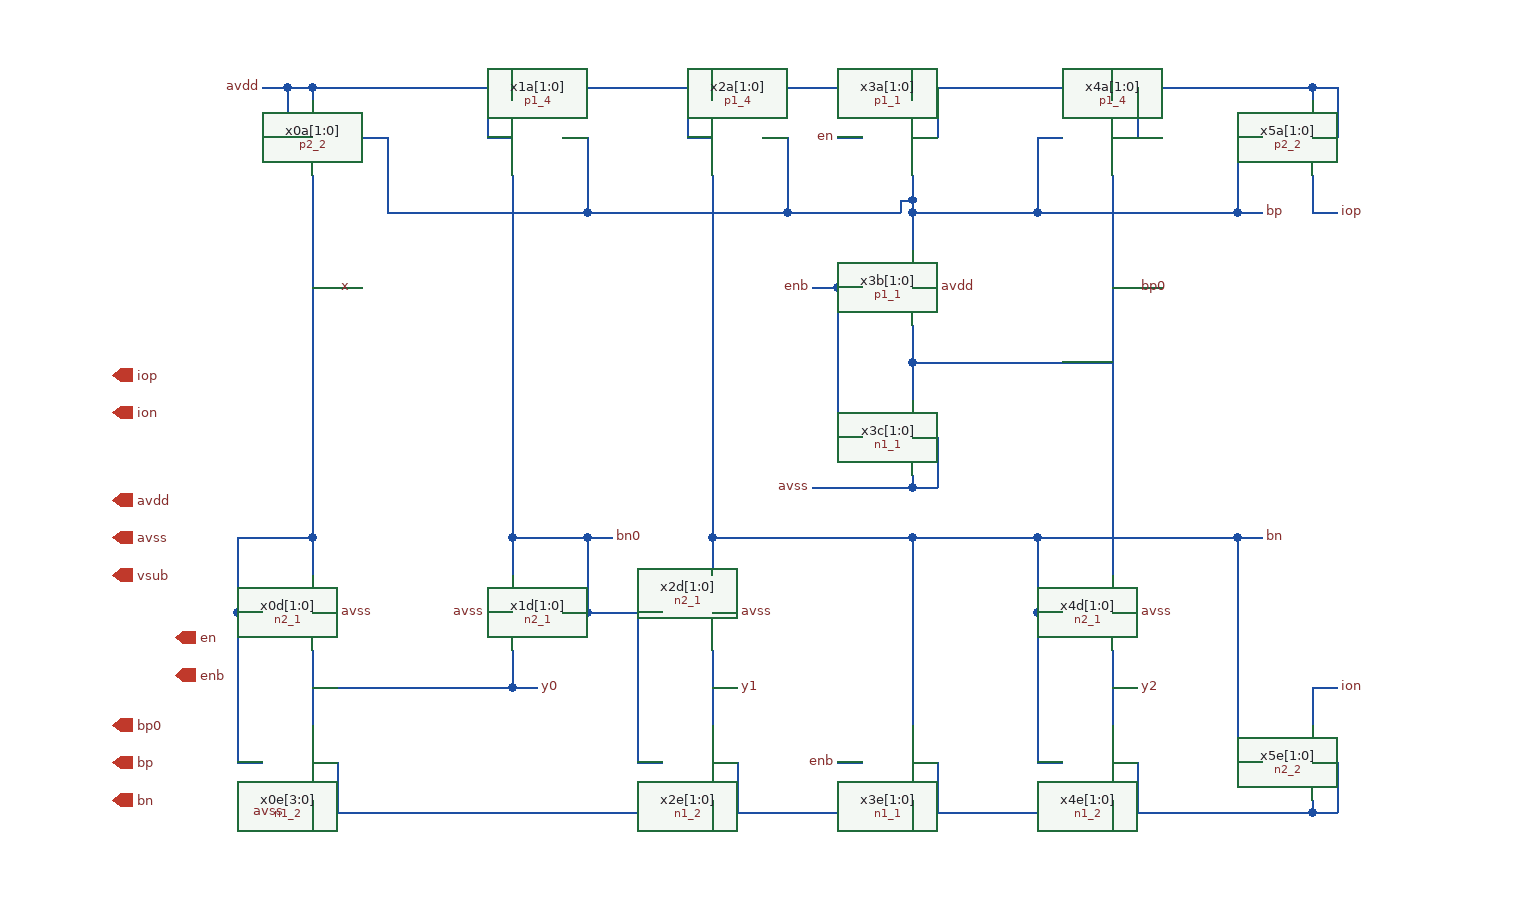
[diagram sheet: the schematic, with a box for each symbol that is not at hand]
v {xschem version=3.4.4 file_version=1.2
}
G {}
K {}
V {}
S {}
E {}
N 220 -660 240 -660 {
lab=bp}
N 240 -660 240 -600 {
lab=bp}
N 400 -660 400 -600 {
lab=bp}
N 380 -660 400 -660 {
lab=bp}
N 920 -660 940 -660 {
lab=bp}
N 920 -660 920 -600 {
lab=bp}
N 120 -340 180 -340 {
lab=bp0}
N 120 -340 120 -280 {
lab=bp0}
N 120 -280 140 -280 {
lab=bp0}
N 120 -280 120 -160 {
lab=bp0}
N 120 -160 140 -160 {
lab=bp0}
N 340 -340 400 -340 {
lab=bn0}
N 400 -340 400 -280 {
lab=bn0}
N 380 -280 400 -280 {
lab=bn0}
N 400 -280 460 -280 {
lab=bn0}
N 440 -280 440 -160 {
lab=bn0}
N 440 -160 460 -160 {
lab=bn0}
N 760 -280 760 -160 {
lab=bn}
N 760 -160 780 -160 {
lab=bn}
N 920 -280 920 -160 {
lab=bn}
N 920 -160 940 -160 {
lab=bn}
N 760 -280 780 -280 {
lab=bn}
N 180 -280 200 -280 { lab=avss}
N 500 -280 520 -280 { lab=avss}
N 500 -160 520 -160 { lab=avss}
N 820 -280 840 -280 { lab=avss}
N 180 -700 340 -700 {
lab=avdd}
N 340 -700 340 -690 {
lab=avdd}
N 340 -700 500 -700 {
lab=avdd}
N 500 -700 500 -690 {
lab=avdd}
N 820 -700 820 -690 {
lab=avdd}
N 820 -700 980 -700 {
lab=avdd}
N 980 -700 980 -690 {
lab=avdd}
N 180 -250 180 -190 {
lab=y0}
N 500 -250 500 -190 {
lab=y1}
N 820 -250 820 -190 {
lab=y2}
N 180 -130 180 -120 {
lab=avss}
N 180 -120 500 -120 {
lab=avss}
N 500 -130 500 -120 {
lab=avss}
N 500 -120 660 -120 {
lab=avss}
N 820 -130 820 -120 {
lab=avss}
N 820 -120 980 -120 {
lab=avss}
N 980 -130 980 -120 {
lab=avss}
N 980 -220 980 -190 {
lab=ion}
N 980 -220 1000 -220 {
lab=ion}
N 980 -630 980 -600 {
lab=iop}
N 980 -600 1000 -600 {
lab=iop}
N 180 -220 340 -220 {
lab=y0}
N 340 -250 340 -220 {
lab=y0}
N 180 -340 180 -310 {
lab=bp0}
N 340 -340 340 -310 {
lab=bn0}
N 760 -340 760 -280 {
lab=bn}
N 400 -340 420 -340 {
lab=bn0}
N 920 -340 940 -340 {
lab=bn}
N 340 -220 360 -220 {
lab=y0}
N 500 -220 520 -220 {
lab=y1}
N 820 -220 840 -220 {
lab=y2}
N 160 -120 180 -120 { lab=avss}
N 320 -280 340 -280 { lab=avss}
N 920 -600 940 -600 {
lab=bp}
N 500 -340 500 -310 {
lab=bn}
N 760 -340 920 -340 {
lab=bn}
N 920 -340 920 -280 {
lab=bn}
N 600 -660 620 -660 { lab=en}
N 580 -540 600 -540 { lab=enb}
N 600 -160 620 -160 { lab=enb}
N 660 -130 660 -120 {
lab=avss}
N 660 -700 660 -690 {
lab=avdd}
N 240 -600 400 -600 {
lab=bp}
N 820 -540 840 -540 {
lab=bp0}
N 660 -510 660 -480 {
lab=bp0}
N 600 -540 620 -540 {
lab=enb}
N 600 -540 600 -420 {
lab=enb}
N 600 -420 620 -420 {
lab=enb}
N 660 -480 660 -450 {
lab=bp0}
N 540 -660 560 -660 {
lab=bp}
N 560 -660 560 -600 {
lab=bp}
N 500 -630 500 -340 {
lab=bn}
N 660 -540 680 -540 { lab=avdd}
N 400 -600 560 -600 {
lab=bp}
N 820 -630 820 -310 {
lab=bp0}
N 560 -600 650 -600 {
lab=bp}
N 650 -610 650 -600 {
lab=bp}
N 650 -610 660 -610 {
lab=bp}
N 660 -630 660 -610 {
lab=bp}
N 660 -610 660 -600 {
lab=bp}
N 660 -600 660 -570 {
lab=bp}
N 500 -700 660 -700 {
lab=avdd}
N 660 -700 820 -700 {
lab=avdd}
N 760 -660 760 -600 {
lab=bp}
N 760 -660 780 -660 {
lab=bp}
N 660 -600 760 -600 {
lab=bp}
N 760 -600 920 -600 {
lab=bp}
N 660 -340 660 -190 {
lab=bn}
N 500 -340 660 -340 {
lab=bn}
N 660 -340 760 -340 {
lab=bn}
N 660 -120 820 -120 {
lab=avss}
N 520 -160 520 -120 {
lab=avss}
N 680 -160 680 -120 {
lab=avss}
N 660 -160 680 -160 {
lab=avss}
N 820 -160 840 -160 {
lab=avss}
N 840 -160 840 -120 {
lab=avss}
N 980 -160 1000 -160 {
lab=avss}
N 1000 -160 1000 -120 {
lab=avss}
N 980 -120 1000 -120 {
lab=avss}
N 200 -160 200 -120 {
lab=avss}
N 180 -160 200 -160 {
lab=avss}
N 680 -420 680 -380 {
lab=avss}
N 660 -380 680 -380 {
lab=avss}
N 660 -420 680 -420 {
lab=avss}
N 660 -390 660 -380 {
lab=avss}
N 580 -380 660 -380 {
lab=avss}
N 160 -700 180 -700 {
lab=avdd}
N 140 -700 160 -700 {
lab=avdd}
N 160 -700 160 -660 {
lab=avdd}
N 160 -660 180 -660 {
lab=avdd}
N 320 -700 320 -660 {
lab=avdd}
N 320 -660 340 -660 {
lab=avdd}
N 480 -700 480 -660 {
lab=avdd}
N 480 -660 500 -660 {
lab=avdd}
N 660 -660 680 -660 {
lab=avdd}
N 680 -700 680 -660 {
lab=avdd}
N 820 -660 840 -660 {
lab=avdd}
N 840 -700 840 -660 {
lab=avdd}
N 980 -660 1000 -660 {
lab=avdd}
N 1000 -700 1000 -660 {
lab=avdd}
N 980 -700 1000 -700 {
lab=avdd}
N 660 -480 820 -480 {
lab=bp0}
N 340 -630 340 -340 {
lab=bn0}
N 180 -630 180 -340 {
lab=bp0}
N 180 -700 180 -690 {
lab=avdd}
N 180 -540 200 -540 {
lab=bp0}
C {devices/title.sym} 160 -40 0 0 {name=l6 author="Luis Henrique Rodovalho"}
C {devices/iopin.sym} 20 -370 2 1 {name=pavdd lab=avdd}
C {devices/iopin.sym} 20 -340 2 1 {name=pavss lab=avss}
C {devices/iopin.sym} 20 -470 2 1 {name=pip lab=iop}
C {devices/iopin.sym} 20 -440 2 1 {name=pim lab=ion}
C {devices/lab_pin.sym} 140 -700 2 1 {name=lavdd1 sig_type=std_logic lab=avdd}
C {devices/iopin.sym} 20 -190 2 1 {name=pbpa lab=bp0}
C {devices/iopin.sym} 20 -160 2 1 {name=pbpb lab=bp}
C {devices/iopin.sym} 20 -130 2 1 {name=pbnb lab=bn}
C {devices/iopin.sym} 20 -310 2 1 {name=pvsub lab=vsub}
C {devices/ipin.sym} 70 -260 2 1 {name=pen lab=en}
C {devices/ipin.sym} 70 -230 2 1 {name=penb lab=enb}
C {p2_2.sym} 200 -660 0 1 {name=x0a[1:0]}
C {p1_4.sym} 360 -660 0 1 {name=x1a[1:0]}
C {p1_4.sym} 520 -660 0 1 {name=x2a[1:0]}
C {p1_4.sym} 800 -660 0 0 {name=x4a[1:0]}
C {p2_2.sym} 960 -660 0 0 {name=x5a[1:0]}
C {n2_1.sym} 160 -280 0 0 {name=x0d[1:0]}
C {n1_2.sym} 160 -160 0 0 {name=x0e[3:0]}
C {n2_1.sym} 360 -280 0 1 {name=x1d[1:0]}
C {n2_1.sym} 480 -280 0 0 {name=x2d[1:0]}
C {n1_2.sym} 480 -160 0 0 {name=x2e[1:0]}
C {n2_1.sym} 800 -280 0 0 {name=x4d[1:0]}
C {n1_2.sym} 800 -160 0 0 {name=x4e[1:0]}
C {n2_2.sym} 960 -160 0 0 {name=x5e[1:0]}
C {devices/lab_pin.sym} 200 -280 2 0 {name=lavss3 sig_type=std_logic lab=avss}
C {devices/lab_pin.sym} 520 -280 2 0 {name=lavss5 sig_type=std_logic lab=avss}
C {devices/lab_pin.sym} 840 -280 2 0 {name=lavss8 sig_type=std_logic lab=avss}
C {devices/lab_pin.sym} 1000 -220 2 0 {name=lavss16 sig_type=std_logic lab=ion}
C {devices/lab_pin.sym} 1000 -600 2 0 {name=lavss17 sig_type=std_logic lab=iop}
C {devices/lab_pin.sym} 840 -540 2 0 {name=lavss18 sig_type=std_logic lab=bp0}
C {devices/lab_pin.sym} 420 -340 2 0 {name=lavss19 sig_type=std_logic lab=bn0}
C {devices/lab_pin.sym} 940 -340 2 0 {name=lavss20 sig_type=std_logic lab=bn}
C {devices/lab_pin.sym} 360 -220 2 0 {name=lavss21 sig_type=std_logic lab=y0}
C {devices/lab_pin.sym} 520 -220 2 0 {name=lavss22 sig_type=std_logic lab=y1}
C {devices/lab_pin.sym} 840 -220 2 0 {name=lavss23 sig_type=std_logic lab=y2}
C {devices/lab_pin.sym} 160 -120 2 1 {name=lavss25 sig_type=std_logic lab=avss}
C {devices/lab_pin.sym} 320 -280 2 1 {name=lavss1 sig_type=std_logic lab=avss}
C {devices/lab_pin.sym} 940 -600 2 0 {name=lavss4 sig_type=std_logic lab=bp}
C {p1_1.sym} 640 -660 0 0 {name=x3a[1:0]}
C {devices/lab_pin.sym} 600 -660 2 1 {name=lavss26 sig_type=std_logic lab=en}
C {devices/lab_pin.sym} 580 -540 2 1 {name=lavss27 sig_type=std_logic lab=enb}
C {n1_1.sym} 640 -420 0 0 {name=x3c[1:0]}
C {devices/lab_pin.sym} 580 -380 2 1 {name=lavss31 sig_type=std_logic lab=avss}
C {n1_1.sym} 640 -160 0 0 {name=x3e[1:0]}
C {devices/lab_pin.sym} 600 -160 2 1 {name=lavss37 sig_type=std_logic lab=enb}
C {p1_1.sym} 640 -540 0 0 {name=x3b[1:0]}
C {devices/lab_pin.sym} 680 -540 2 0 {name=lavss32 sig_type=std_logic lab=avdd}
C {devices/lab_pin.sym} 200 -540 2 0 {name=lavss2 sig_type=std_logic lab=x}
